VERSION 5.8 ;
BUSBITCHARS "[]" ;
DIVIDERCHAR "/" ;

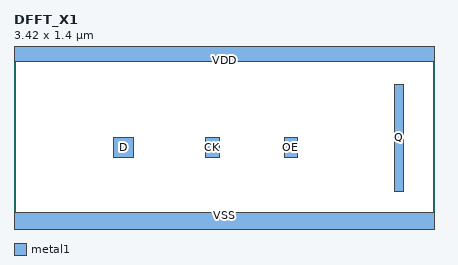
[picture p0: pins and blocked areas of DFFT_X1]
MACRO DFFT_X1
  CLASS CORE ;
  ORIGIN 0 0 ;
  FOREIGN DFFT_X1 0 0 ;
  SIZE 3.42 BY 1.4 ;
  SYMMETRY X Y ;
  SITE FreePDK45_38x28_10R_NP_162NW_34O ;
  PIN D
    DIRECTION INPUT ;
    USE SIGNAL ;
    PORT
      LAYER metal1 ;
        RECT 0.81 0.53 0.97 0.7 ;
    END
  END D
  PIN CK
    DIRECTION INPUT ;
    USE SIGNAL ;
    PORT
      LAYER metal1 ;
        RECT 1.56 0.53 1.67 0.7 ;
    END
  END CK
  PIN OE
    DIRECTION INPUT ;
    USE SIGNAL ;
    PORT
      LAYER metal1 ;
        RECT 2.2 0.53 2.31 0.7 ;
    END
  END OE
  PIN Q
    DIRECTION OUTPUT TRISTATE ;
    USE SIGNAL ;
    PORT
      LAYER metal1 ;
        RECT 3.1 0.26 3.17 1.13 ;
    END
  END Q
  PIN VDD
    DIRECTION INOUT ;
    USE POWER ;
    SHAPE ABUTMENT ;
    PORT
      LAYER metal1 ;
        RECT 0 1.315 3.42 1.485 ;
    END
  END VDD
  PIN VSS
    DIRECTION INOUT ;
    USE GROUND ;
    SHAPE ABUTMENT ;
    PORT
      LAYER metal1 ;
        RECT 0 -0.085 3.42 0.085 ;
    END
  END VSS
END DFFT_X1

END LIBRARY
